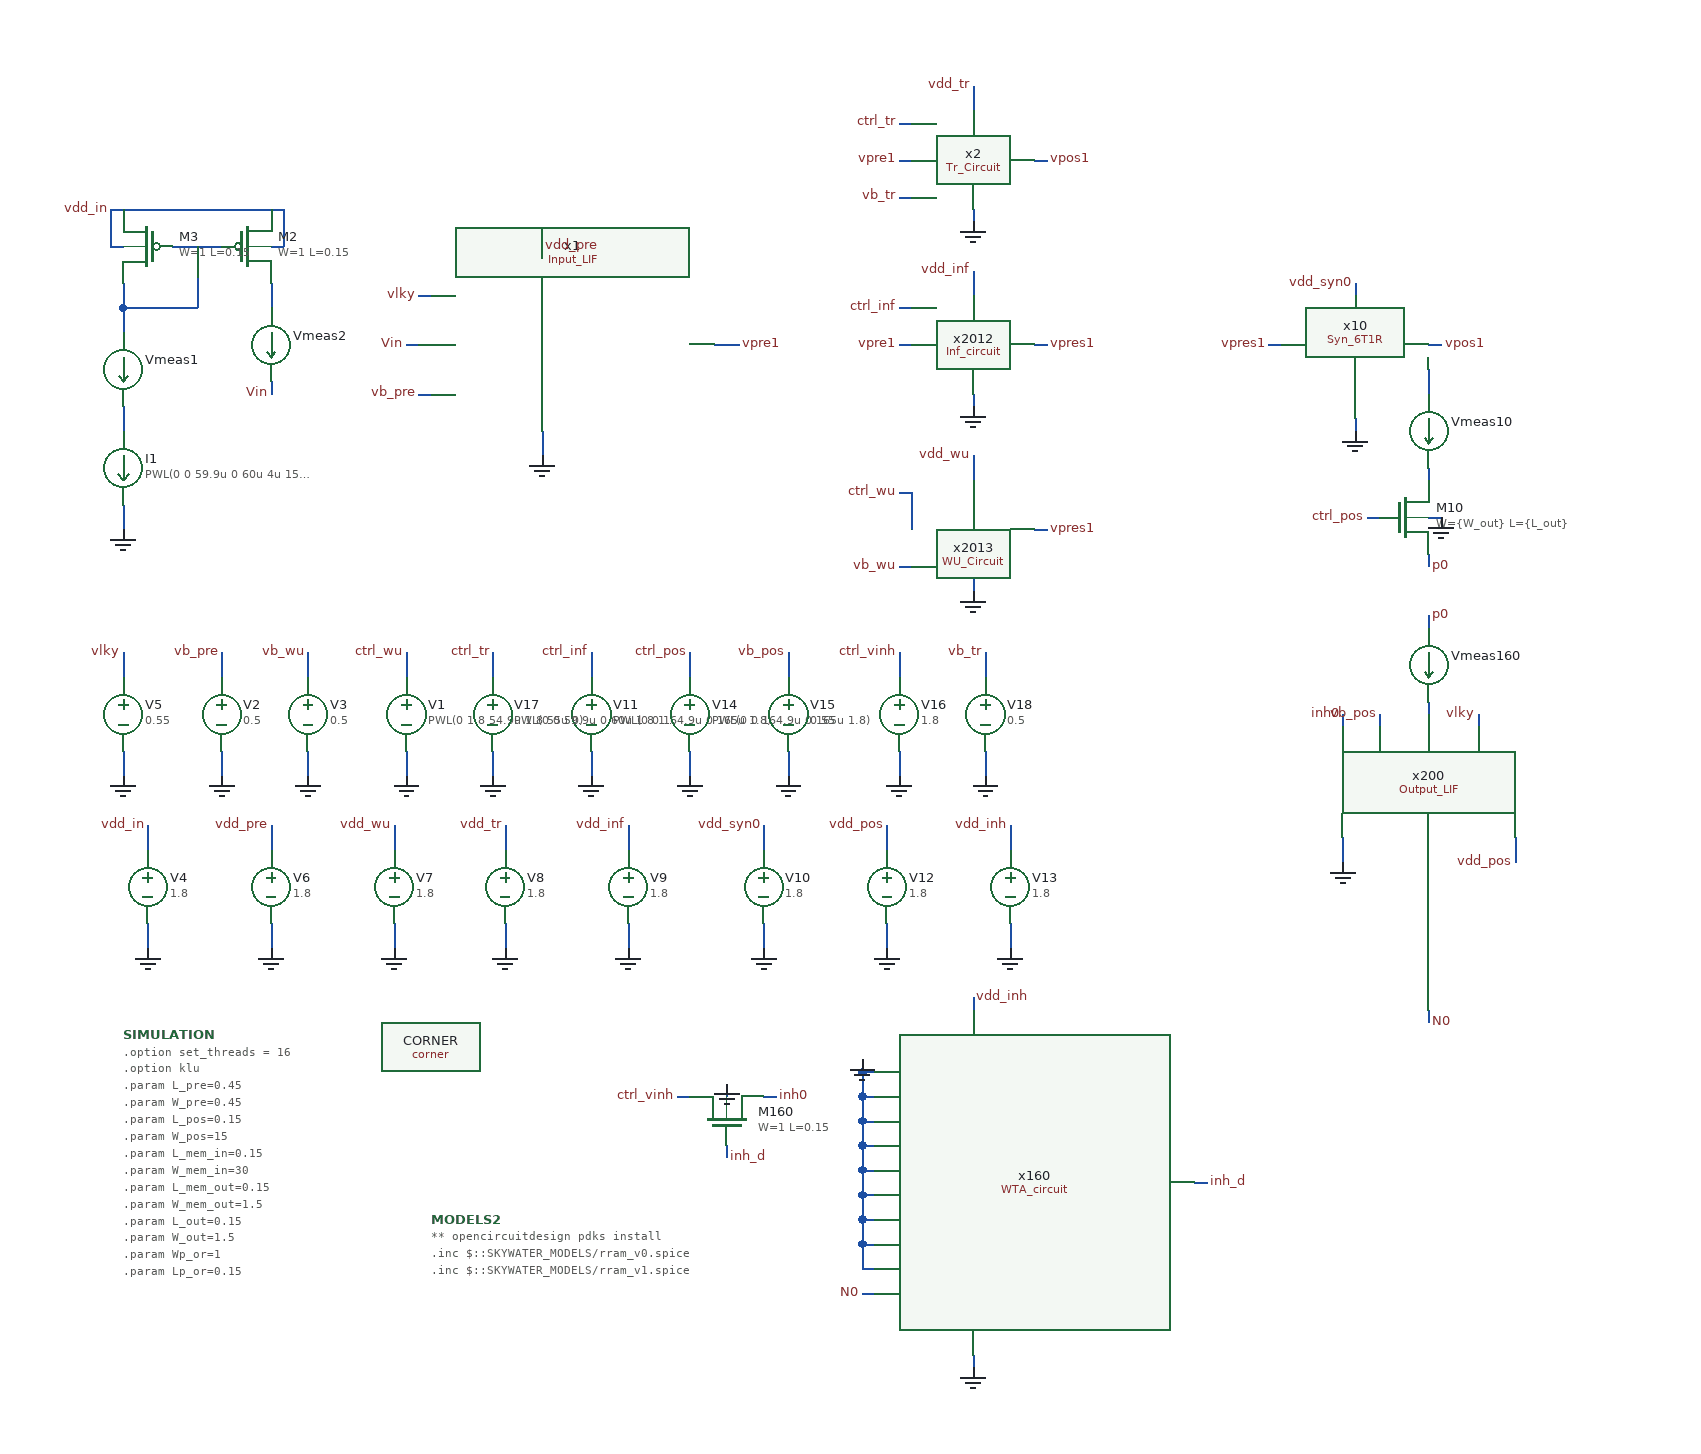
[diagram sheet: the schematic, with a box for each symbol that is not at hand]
v {xschem version=3.4.5 file_version=1.2
}
G {}
K {}
V {}
S {}
E {}
B 2 -1460 -1640 -660 -1240 {flags=graph
y1=-9.77708e-08
y2=2.18663e-06
ypos1=0
ypos2=2
divy=5
subdivy=1
unity=1
x1=0
x2=0.0004
divx=5
subdivx=1
xlabmag=1.0
ylabmag=1.0


dataset=-1
unitx=1
logx=0
logy=0



color=4
node=i(Vmeas1)}
B 2 -1460 -1240 -660 -840 {flags=graph
y1=-0.014
y2=1.8
ypos1=0
ypos2=2
divy=5
subdivy=1
unity=1
x1=0
x2=0.0004
divx=5
subdivx=1
xlabmag=1.0
ylabmag=1.0


dataset=-1
unitx=1
logx=0
logy=0
color="4 6"
node="vpos1
vpres1"}
B 2 -660 -1240 140 -840 {flags=graph
y1=0.00014
y2=1.6
ypos1=0
ypos2=2
divy=5
subdivy=1
unity=1
x1=0
x2=0.0004
divx=5
subdivx=1
xlabmag=1.0
ylabmag=1.0


dataset=-1
unitx=1
logx=0
logy=0


color=7
node=Vin}
B 2 -660 -1640 140 -1240 {flags=graph
y1=-7e-05
y2=0.00015
ypos1=0
ypos2=2
divy=5
subdivy=1
unity=1
x1=0
x2=0.0004
divx=5
subdivx=1
xlabmag=1.0
ylabmag=1.0


dataset=-1
unitx=1
logx=0
logy=0







color=17
node="\\"-1.8 i(v1) *\\""}
B 2 -1460 -840 -660 -440 {flags=graph
y1=1.1
y2=5.3
ypos1=0
ypos2=2
divy=5
subdivy=1
unity=1
x1=0
x2=0.0004
divx=5
subdivx=1
xlabmag=1.0
ylabmag=1.0


dataset=-1
unitx=1
logx=0
logy=0

color=6
node="\\"S10; 5 n.x10.xr1.n1#ngap -\\""}
B 2 -660 -840 140 -440 {flags=graph
y1=0
y2=1.8
ypos1=0
ypos2=2
divy=5
subdivy=1
unity=1
x1=0
x2=0.0004
divx=5
subdivx=1
xlabmag=1.0
ylabmag=1.0


dataset=-1
unitx=1
logx=0
logy=0



color="4 6 7"
node="ctrl_inf
ctrl_tr
ctrl_wu"}
B 2 -1460 -440 -660 -40 {flags=graph
y1=-4.6e-07
y2=8.2e-06
ypos1=0
ypos2=2
divy=5
subdivy=1
unity=1
x1=0
x2=0.0004
divx=5
subdivx=1
xlabmag=1.0
ylabmag=1.0


dataset=-1
unitx=1
logx=0
logy=0

color=6
node=\\"i(Vmeas160)\\"}
B 2 -660 -440 140 -40 {flags=graph
y1=-0.42215
y2=1.75283
ypos1=0
ypos2=2
divy=5
subdivy=1
unity=1
x1=0
x2=0.0004
divx=5
subdivx=1
xlabmag=1.0
ylabmag=1.0


dataset=-1
unitx=1
logx=0
logy=0

color="6 4"
node="\\"p0\\"
\\"N0\\""}
N -2180 -1390 -2160 -1390 {
lab=vpre1}
N -2580 -1140 -2580 -1120 {
lab=vb_pre}
N -2580 -1060 -2580 -1040 {
lab=GND}
N -2660 -1260 -2660 -1240 {
lab=GND}
N -2540 -1440 -2540 -1420 {
lab=#net1}
N -2540 -1470 -2530 -1470 {
lab=vdd_in}
N -2530 -1500 -2530 -1470 {
lab=vdd_in}
N -2540 -1500 -2530 -1500 {
lab=vdd_in}
N -2620 -1470 -2580 -1470 {
lab=#net2}
N -2660 -1500 -2540 -1500 {
lab=vdd_in}
N -2670 -1470 -2660 -1470 {
lab=vdd_in}
N -2670 -1500 -2670 -1470 {
lab=vdd_in}
N -2670 -1500 -2660 -1500 {
lab=vdd_in}
N -2660 -1440 -2660 -1420 {
lab=#net2}
N -2660 -1420 -2600 -1420 {
lab=#net2}
N -2600 -1470 -2600 -1420 {
lab=#net2}
N -2660 -1340 -2660 -1320 {
lab=#net3}
N -2660 -1420 -2660 -1400 {
lab=#net2}
N -2640 -1000 -2640 -980 {
lab=vdd_in}
N -2640 -920 -2640 -900 {
lab=GND}
N -2320 -1320 -2320 -1300 {
lab=GND}
N -2420 -1350 -2410 -1350 {
lab=vb_pre}
N -2540 -1360 -2540 -1350 {
lab=Vin}
N -2430 -1390 -2420 -1390 {
lab=Vin}
N -2420 -1430 -2410 -1430 {
lab=vlky}
N -2660 -1140 -2660 -1120 {
lab=vlky}
N -2660 -1060 -2660 -1040 {
lab=GND}
N -2320 -1470 -2320 -1460 {
lab=vdd_pre}
N -1660 -1330 -1660 -1320 {
lab=GND}
N -1660 -1440 -1660 -1430 {
lab=vdd_syn0}
N -1600 -1250 -1590 -1250 {
lab=GND}
N -1600 -1220 -1600 -1210 {
lab=p0}
N -1730 -1390 -1720 -1390 {
lab=vpres1}
N -1600 -1390 -1590 -1390 {
lab=vpos1}
N -1970 -1200 -1970 -1190 {
lab=GND}
N -1920 -1240 -1910 -1240 {
lab=vpres1}
N -1970 -1350 -1970 -1340 {
lab=GND}
N -1920 -1390 -1910 -1390 {
lab=vpres1}
N -1650 -1250 -1640 -1250 {
lab=ctrl_pos}
N -2030 -1210 -2020 -1210 {
lab=vb_wu}
N -1600 -1370 -1600 -1350 {
lab=#net4}
N -1600 -1290 -1600 -1280 {
lab=#net5}
N -2030 -1420 -2020 -1420 {
lab=ctrl_inf}
N -1970 -1300 -1970 -1280 {
lab=vdd_wu}
N -1970 -1450 -1970 -1430 {
lab=vdd_inf}
N -2030 -1270 -2020 -1270 {
lab=ctrl_wu}
N -2020 -1270 -2020 -1240 {
lab=ctrl_wu}
N -2030 -1390 -2020 -1390 {
lab=vpre1}
N -2540 -1000 -2540 -980 {
lab=vdd_pre}
N -2540 -920 -2540 -900 {
lab=GND}
N -2440 -1000 -2440 -980 {
lab=vdd_wu}
N -2440 -920 -2440 -900 {
lab=GND}
N -2350 -1000 -2350 -980 {
lab=vdd_tr}
N -2350 -920 -2350 -900 {
lab=GND}
N -2250 -1000 -2250 -980 {
lab=vdd_inf}
N -2250 -920 -2250 -900 {
lab=GND}
N -2140 -1000 -2140 -980 {
lab=vdd_syn0}
N -2140 -920 -2140 -900 {
lab=GND}
N -2430 -1140 -2430 -1120 {
lab=ctrl_wu}
N -2430 -1060 -2430 -1040 {
lab=GND}
N -2510 -1140 -2510 -1120 {
lab=vb_wu}
N -2510 -1060 -2510 -1040 {
lab=GND}
N -2280 -1140 -2280 -1120 {
lab=ctrl_inf}
N -2280 -1060 -2280 -1040 {
lab=GND}
N -1600 -1100 -1600 -1090 {
lab=#net6}
N -1600 -1170 -1600 -1160 {
lab=p0}
N -1600 -850 -1600 -840 {
lab=N0}
N -1670 -990 -1670 -970 {
lab=GND}
N -1530 -990 -1530 -970 {
lab=vdd_pos}
N -1670 -1090 -1670 -1080 {
lab=inh0}
N -1640 -1090 -1640 -1080 {
lab=vb_pos}
N -1560 -1090 -1560 -1080 {
lab=vlky}
N -1970 -860 -1970 -850 {
lab=vdd_inh}
N -1970 -570 -1970 -560 {
lab=GND}
N -1790 -710 -1780 -710 {
lab=inh_d}
N -2060 -620 -2050 -620 {
lab=N0}
N -2140 -780 -2130 -780 {
lab=inh0}
N -2170 -790 -2170 -780 {
lab=GND}
N -2170 -740 -2170 -730 {
lab=inh_d}
N -2210 -780 -2200 -780 {
lab=ctrl_vinh}
N -2040 -1000 -2040 -980 {
lab=vdd_pos}
N -2040 -920 -2040 -900 {
lab=GND}
N -1940 -1000 -1940 -980 {
lab=vdd_inh}
N -1940 -920 -1940 -900 {
lab=GND}
N -2060 -810 -2060 -800 {
lab=GND}
N -2060 -800 -2050 -800 {
lab=GND}
N -2060 -640 -2050 -640 {
lab=GND}
N -2060 -660 -2060 -640 {
lab=GND}
N -2060 -660 -2050 -660 {
lab=GND}
N -2060 -680 -2060 -660 {
lab=GND}
N -2060 -680 -2050 -680 {
lab=GND}
N -2060 -700 -2060 -680 {
lab=GND}
N -2060 -700 -2050 -700 {
lab=GND}
N -2060 -720 -2060 -700 {
lab=GND}
N -2060 -720 -2050 -720 {
lab=GND}
N -2060 -740 -2060 -720 {
lab=GND}
N -2060 -740 -2050 -740 {
lab=GND}
N -2060 -760 -2060 -740 {
lab=GND}
N -2060 -760 -2050 -760 {
lab=GND}
N -2060 -780 -2060 -760 {
lab=GND}
N -2060 -780 -2050 -780 {
lab=GND}
N -2060 -800 -2060 -780 {
lab=GND}
N -2200 -1140 -2200 -1120 {
lab=ctrl_pos}
N -2200 -1060 -2200 -1040 {
lab=GND}
N -2120 -1140 -2120 -1120 {
lab=vb_pos}
N -2120 -1060 -2120 -1040 {
lab=GND}
N -2030 -1140 -2030 -1120 {
lab=ctrl_vinh}
N -2030 -1060 -2030 -1040 {
lab=GND}
N -1970 -1500 -1970 -1490 {
lab=GND}
N -1920 -1540 -1910 -1540 {
lab=vpos1}
N -2030 -1510 -2020 -1510 {
lab=vb_tr}
N -1970 -1600 -1970 -1580 {
lab=vdd_tr}
N -2030 -1570 -2020 -1570 {
lab=ctrl_tr}
N -2030 -1540 -2020 -1540 {
lab=vpre1}
N -2360 -1140 -2360 -1120 {
lab=ctrl_tr}
N -2360 -1060 -2360 -1040 {
lab=GND}
N -1960 -1140 -1960 -1120 {
lab=vb_tr}
N -1960 -1060 -1960 -1040 {
lab=GND}
C {devices/gnd.sym} -2320 -1300 0 0 {name=l1 lab=GND}
C {devices/lab_pin.sym} -2420 -1350 0 0 {name=p3 sig_type=std_logic lab=vb_pre}
C {devices/lab_pin.sym} -2160 -1390 2 0 {name=p5 sig_type=std_logic lab=vpre1}
C {devices/vsource.sym} -2580 -1090 0 0 {name=V2 value=0.5 savecurrent=false}
C {devices/lab_pin.sym} -2580 -1140 0 0 {name=p6 sig_type=std_logic lab=vb_pre}
C {devices/gnd.sym} -2580 -1040 0 0 {name=l4 lab=GND}
C {devices/code_shown.sym} -2660 -830 0 0 {name=SIMULATION
only_toplevel=true
value="
.option set_threads = 16
.option klu
.param L_pre=0.45
.param W_pre=0.45
.param L_pos=0.15
.param W_pos=15
.param L_mem_in=0.15
.param W_mem_in=30
.param L_mem_out=0.15
.param W_mem_out=1.5
.param L_out=0.15
.param W_out=1.5
.param Wp_or=1
.param Lp_or=0.15
.param Wn_or=1
.param Ln_or=0.15
.param Wp_or_inv=1
.param Lp_or_inv=0.15
.param Wn_or_inv=1
.param Ln_or_inv=0.15
.control
	save all
	tran 10n 400u 0
	write Input_LIF_tb.raw
.endc
" }
C {sky130_fd_pr/corner.sym} -2410 -820 0 0 {name=CORNER only_toplevel=true corner=tt}
C {devices/isource.sym} -2660 -1290 0 1 {name=I1 value="PWL(0 0 59.9u 0 60u 4u 159.9u 4u 160u 0 164.9u 0 165u 4u 389.9u 4u 390u 0)"

}
C {devices/gnd.sym} -2660 -1240 0 0 {name=l20 lab=GND}
C {sky130_fd_pr/pfet_01v8.sym} -2560 -1470 0 0 {name=M2
L=0.15
W=1
nf=1
mult=1
ad="'int((nf+1)/2) * W/nf * 0.29'" 
pd="'2*int((nf+1)/2) * (W/nf + 0.29)'"
as="'int((nf+2)/2) * W/nf * 0.29'" 
ps="'2*int((nf+2)/2) * (W/nf + 0.29)'"
nrd="'0.29 / W'" nrs="'0.29 / W'"
sa=0 sb=0 sd=0
model=pfet_01v8
spiceprefix=X
}
C {sky130_fd_pr/pfet_01v8.sym} -2640 -1470 0 1 {name=M3
L=0.15
W=1
nf=1
mult=1
ad="'int((nf+1)/2) * W/nf * 0.29'" 
pd="'2*int((nf+1)/2) * (W/nf + 0.29)'"
as="'int((nf+2)/2) * W/nf * 0.29'" 
ps="'2*int((nf+2)/2) * (W/nf + 0.29)'"
nrd="'0.29 / W'" nrs="'0.29 / W'"
sa=0 sb=0 sd=0
model=pfet_01v8
spiceprefix=X
}
C {devices/lab_pin.sym} -2540 -1350 0 0 {name=p10 sig_type=std_logic lab=Vin}
C {devices/ammeter.sym} -2660 -1370 0 0 {name=Vmeas1 savecurrent=true}
C {devices/ammeter.sym} -2540 -1390 0 0 {name=Vmeas2 savecurrent=true}
C {devices/vsource.sym} -2640 -950 0 0 {name=V4 savecurrent=false value=1.8
*"PWL(0 0 39.9u 0 40u 1.8)"}
C {devices/lab_pin.sym} -2640 -1000 0 0 {name=p1 sig_type=std_logic lab=vdd_in}
C {devices/gnd.sym} -2640 -900 0 0 {name=l6 lab=GND}
C {devices/lab_pin.sym} -2430 -1390 0 0 {name=p8 sig_type=std_logic lab=Vin}
C {devices/lab_pin.sym} -2420 -1430 0 0 {name=p11 sig_type=std_logic lab=vlky}
C {devices/vsource.sym} -2660 -1090 0 0 {name=V5 savecurrent=false value=0.55}
C {devices/lab_pin.sym} -2660 -1140 0 0 {name=p13 sig_type=std_logic lab=vlky}
C {devices/gnd.sym} -2660 -1040 0 0 {name=l9 lab=GND}
C {devices/launcher.sym} -2340 -550 0 0 {name=h5
descr="load waves" 
tclcommand="xschem raw_read $netlist_dir/Input_LIF_tb.raw tran"
}
C {/home/ricardo/RATT_repos/Proyectos_xschem/SNN/Input_LIF.sym} -2320 -1390 0 0 {name=x1}
C {devices/lab_pin.sym} -1910 -1540 2 0 {name=p162 sig_type=std_logic lab=vpos1}
C {devices/gnd.sym} -1660 -1320 0 0 {name=l39 lab=GND}
C {devices/lab_pin.sym} -1730 -1390 0 0 {name=p26 sig_type=std_logic lab=vpres1}
C {devices/ammeter.sym} -1600 -1320 0 0 {name=Vmeas10 savecurrent=true}
C {sky130_fd_pr/nfet_01v8.sym} -1620 -1250 0 0 {name=M10
L=\{L_out\}
W=\{W_out\}
nf=1 
mult=1
ad="'int((nf+1)/2) * W/nf * 0.29'" 
pd="'2*int((nf+1)/2) * (W/nf + 0.29)'"
as="'int((nf+2)/2) * W/nf * 0.29'" 
ps="'2*int((nf+2)/2) * (W/nf + 0.29)'"
nrd="'0.29 / W'" nrs="'0.29 / W'"
sa=0 sb=0 sd=0
model=nfet_01v8
spiceprefix=X
}
C {devices/gnd.sym} -1590 -1250 3 0 {name=l8 lab=GND}
C {devices/lab_pin.sym} -1600 -1210 2 0 {name=p46 sig_type=std_logic lab=p0}
C {devices/lab_pin.sym} -1910 -1240 2 0 {name=p35 sig_type=std_logic lab=vpres1}
C {devices/gnd.sym} -1970 -1190 0 0 {name=l18 lab=GND}
C {devices/lab_pin.sym} -2030 -1390 0 0 {name=p41 sig_type=std_logic lab=vpre1}
C {devices/lab_pin.sym} -2030 -1420 0 0 {name=p42 sig_type=std_logic lab=ctrl_inf}
C {devices/gnd.sym} -1970 -1340 0 0 {name=l10 lab=GND}
C {devices/lab_pin.sym} -1970 -1300 0 0 {name=p47 sig_type=std_logic lab=vdd_wu}
C {devices/lab_pin.sym} -1970 -1450 0 0 {name=p48 sig_type=std_logic lab=vdd_inf}
C {devices/lab_pin.sym} -1650 -1250 0 0 {name=p78 sig_type=std_logic lab=ctrl_pos}
C {/home/ricardo/RATT_repos/Proyectos_xschem/SNN/Syn_6T1R.sym} -1600 -1210 0 0 {name=x10}
C {devices/lab_pin.sym} -1660 -1440 0 0 {name=p63 sig_type=std_logic lab=vdd_syn0}
C {/home/ricardo/RATT_repos/Proyectos_xschem/SNN/Inf_circuit.sym} -1970 -1390 0 0 {name=x2012}
C {/home/ricardo/RATT_repos/Proyectos_xschem/SNN/WU_Circuit.sym} -1970 -1240 0 0 {name=x2013}
C {devices/lab_pin.sym} -2030 -1270 0 0 {name=p36 sig_type=std_logic lab=ctrl_wu}
C {devices/lab_pin.sym} -2030 -1210 0 0 {name=p283 sig_type=std_logic lab=vb_wu}
C {devices/lab_pin.sym} -1590 -1390 2 0 {name=p405 sig_type=std_logic lab=vpos1}
C {devices/vsource.sym} -2540 -950 0 0 {name=V6 savecurrent=false value=1.8
*"PWL(0 0 39.9u 0 40u 1.8)"}
C {devices/lab_pin.sym} -2540 -1000 0 0 {name=p2 sig_type=std_logic lab=vdd_pre}
C {devices/gnd.sym} -2540 -900 0 0 {name=l11 lab=GND}
C {devices/vsource.sym} -2440 -950 0 0 {name=V7 
value=1.8}
C {devices/gnd.sym} -2440 -900 0 0 {name=l3 lab=GND}
C {devices/lab_pin.sym} -2670 -1500 0 0 {name=p4 sig_type=std_logic lab=vdd_in}
C {devices/lab_pin.sym} -2440 -1000 0 0 {name=p9 sig_type=std_logic lab=vdd_wu}
C {devices/vsource.sym} -2350 -950 0 0 {name=V8 
value=1.8}
C {devices/gnd.sym} -2350 -900 0 0 {name=l7 lab=GND}
C {devices/lab_pin.sym} -2350 -1000 0 0 {name=p12 sig_type=std_logic lab=vdd_tr}
C {devices/vsource.sym} -2250 -950 0 0 {name=V9 
value=1.8}
C {devices/gnd.sym} -2250 -900 0 0 {name=l12 lab=GND}
C {devices/lab_pin.sym} -2250 -1000 0 0 {name=p14 sig_type=std_logic lab=vdd_inf}
C {devices/vsource.sym} -2140 -950 0 0 {name=V10 
value=1.8}
C {devices/gnd.sym} -2140 -900 0 0 {name=l14 lab=GND}
C {devices/lab_pin.sym} -2140 -1000 0 0 {name=p15 sig_type=std_logic lab=vdd_syn0}
C {devices/lab_pin.sym} -2320 -1470 2 0 {name=p7 sig_type=std_logic lab=vdd_pre}
C {devices/vsource.sym} -2430 -1090 0 0 {name=V1 savecurrent=false value="PWL(0 1.8 54.9u 1.8 55u 0)"}
C {devices/lab_pin.sym} -2430 -1140 0 0 {name=p16 sig_type=std_logic lab=ctrl_wu}
C {devices/gnd.sym} -2430 -1040 0 0 {name=l2 lab=GND}
C {devices/vsource.sym} -2510 -1090 0 0 {name=V3 savecurrent=false value=0.5}
C {devices/lab_pin.sym} -2510 -1140 0 0 {name=p17 sig_type=std_logic lab=vb_wu}
C {devices/gnd.sym} -2510 -1040 0 0 {name=l5 lab=GND}
C {devices/vsource.sym} -2280 -1090 0 0 {name=V11 savecurrent=false value="PWL(0 0 164.9u 0 165u 1.8)"}
C {devices/lab_pin.sym} -2280 -1140 0 0 {name=p18 sig_type=std_logic lab=ctrl_inf}
C {devices/gnd.sym} -2280 -1040 0 0 {name=l15 lab=GND}
C {devices/lab_pin.sym} -1640 -1090 1 0 {name=p19 sig_type=std_logic lab=vb_pos}
C {devices/gnd.sym} -1670 -970 0 0 {name=l16 lab=GND}
C {devices/ammeter.sym} -1600 -1130 0 0 {name=Vmeas160 savecurrent=true}
C {devices/lab_pin.sym} -1600 -1170 2 0 {name=p20 sig_type=std_logic lab=p0}
C {devices/lab_pin.sym} -1600 -840 2 0 {name=p21 sig_type=std_logic lab=N0}
C {devices/lab_pin.sym} -1530 -970 3 0 {name=p22 sig_type=std_logic lab=vdd_pos}
C {devices/lab_pin.sym} -1670 -1090 1 0 {name=p23 sig_type=std_logic lab=inh0}
C {devices/lab_pin.sym} -1560 -1090 1 0 {name=p24 sig_type=std_logic lab=vlky}
C {/home/ricardo/RATT_repos/Proyectos_xschem/SNN/Output_LIF.sym} -1600 -990 1 0 {name=x200}
C {devices/gnd.sym} -1970 -560 0 0 {name=l27 lab=GND}
C {devices/lab_pin.sym} -1970 -860 2 0 {name=p81 sig_type=std_logic lab=vdd_inh}
C {devices/lab_pin.sym} -1780 -710 2 0 {name=p91 sig_type=std_logic lab=inh_d}
C {/home/ricardo/RATT_repos/Proyectos_xschem/inhibitory/WTA_circuit.sym} -1930 -710 0 0 {name=x160}
C {devices/lab_pin.sym} -2060 -620 0 0 {name=p25 sig_type=std_logic lab=N0}
C {devices/lab_pin.sym} -2130 -780 2 0 {name=p31 sig_type=std_logic lab=inh0}
C {sky130_fd_pr/nfet_01v8.sym} -2170 -760 3 0 {name=M160
L=0.15
W=1
nf=1 
mult=1
ad="'int((nf+1)/2) * W/nf * 0.29'" 
pd="'2*int((nf+1)/2) * (W/nf + 0.29)'"
as="'int((nf+2)/2) * W/nf * 0.29'" 
ps="'2*int((nf+2)/2) * (W/nf + 0.29)'"
nrd="'0.29 / W'" nrs="'0.29 / W'"
sa=0 sb=0 sd=0
model=nfet_01v8
spiceprefix=X
}
C {devices/gnd.sym} -2170 -790 2 0 {name=l21 lab=GND}
C {devices/lab_pin.sym} -2170 -730 2 0 {name=p32 sig_type=std_logic lab=inh_d}
C {devices/lab_pin.sym} -2210 -780 0 0 {name=p45 sig_type=std_logic lab=ctrl_vinh}
C {devices/vsource.sym} -2040 -950 0 0 {name=V12 
value=1.8}
C {devices/gnd.sym} -2040 -900 0 0 {name=l17 lab=GND}
C {devices/lab_pin.sym} -2040 -1000 0 0 {name=p27 sig_type=std_logic lab=vdd_pos}
C {devices/vsource.sym} -1940 -950 0 0 {name=V13 
value=1.8}
C {devices/gnd.sym} -1940 -900 0 0 {name=l19 lab=GND}
C {devices/lab_pin.sym} -1940 -1000 0 0 {name=p28 sig_type=std_logic lab=vdd_inh}
C {devices/gnd.sym} -2060 -810 2 0 {name=l22 lab=GND}
C {devices/vsource.sym} -2200 -1090 0 0 {name=V14 savecurrent=false value="PWL(0 0 164.9u 0 165u 1.8)"}
C {devices/lab_pin.sym} -2200 -1140 0 0 {name=p29 sig_type=std_logic lab=ctrl_pos}
C {devices/gnd.sym} -2200 -1040 0 0 {name=l23 lab=GND}
C {devices/vsource.sym} -2120 -1090 0 0 {name=V15 savecurrent=false value=0.55}
C {devices/lab_pin.sym} -2120 -1140 0 0 {name=p30 sig_type=std_logic lab=vb_pos}
C {devices/gnd.sym} -2120 -1040 0 0 {name=l24 lab=GND}
C {devices/vsource.sym} -2030 -1090 0 0 {name=V16 savecurrent=false value=1.8}
C {devices/lab_pin.sym} -2030 -1140 0 0 {name=p33 sig_type=std_logic lab=ctrl_vinh}
C {devices/gnd.sym} -2030 -1040 0 0 {name=l25 lab=GND}
C {devices/code.sym} -2410 -680 0 0 {name=MODELS2
only_toplevel=true
format="tcleval( @value )"
value="
** opencircuitdesign pdks install
.inc $::SKYWATER_MODELS/rram_v0.spice
.inc $::SKYWATER_MODELS/rram_v1.spice
"
spice_ignore=false}
C {/home/ricardo/RATT_repos/Proyectos_xschem/SNN/Tr_Circuit.sym} -1970 -1540 0 0 {name=x2}
C {devices/lab_pin.sym} -1910 -1390 2 0 {name=p34 sig_type=std_logic lab=vpres1}
C {devices/gnd.sym} -1970 -1490 0 0 {name=l13 lab=GND}
C {devices/lab_pin.sym} -1970 -1600 0 0 {name=p37 sig_type=std_logic lab=vdd_tr}
C {devices/lab_pin.sym} -2030 -1570 0 0 {name=p38 sig_type=std_logic lab=ctrl_tr}
C {devices/lab_pin.sym} -2030 -1510 0 0 {name=p39 sig_type=std_logic lab=vb_tr}
C {devices/vsource.sym} -2360 -1090 0 0 {name=V17 savecurrent=false value="PWL(0 0 59.9u 0 60u 1.8 159.9u 1.8 160u 0)"}
C {devices/lab_pin.sym} -2360 -1140 0 0 {name=p43 sig_type=std_logic lab=ctrl_tr}
C {devices/gnd.sym} -2360 -1040 0 0 {name=l26 lab=GND}
C {devices/vsource.sym} -1960 -1090 0 0 {name=V18 savecurrent=false value=0.5}
C {devices/lab_pin.sym} -1960 -1140 0 0 {name=p44 sig_type=std_logic lab=vb_tr}
C {devices/gnd.sym} -1960 -1040 0 0 {name=l28 lab=GND}
C {devices/lab_pin.sym} -2030 -1540 0 0 {name=p40 sig_type=std_logic lab=vpre1}
